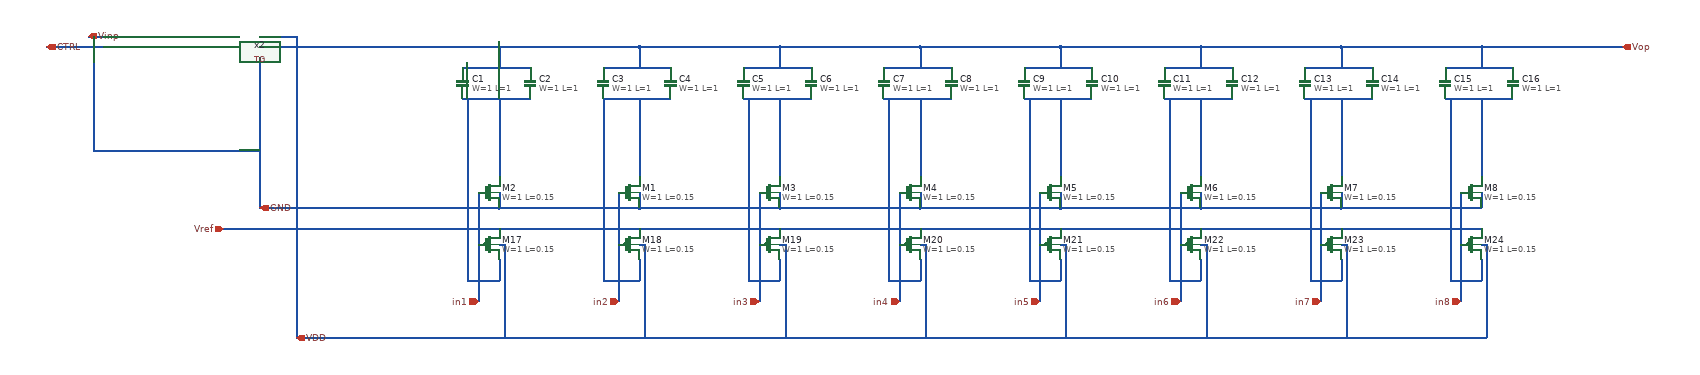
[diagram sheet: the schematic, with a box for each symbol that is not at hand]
v {xschem version=3.4.8RC file_version=1.2}
G {}
K {}
V {}
S {}
E {}
N -20 -30 110 -30 {lab=Vop}
N -20 30 110 30 {lab=#net1}
N 50 30 50 70 {lab=#net1}
N 50 -70 50 -30 {lab=Vop}
N 250 -30 380 -30 {lab=Vop}
N 250 30 380 30 {lab=#net2}
N 320 30 320 70 {lab=#net2}
N 320 -70 320 -30 {lab=Vop}
N 50 -70 320 -70 {lab=Vop}
N 320 -70 590 -70 {lab=Vop}
N 520 -30 650 -30 {lab=Vop}
N 520 30 650 30 {lab=#net3}
N 590 30 590 70 {lab=#net3}
N 590 -70 590 -30 {lab=Vop}
N 790 -30 920 -30 {lab=Vop}
N 790 30 920 30 {lab=#net4}
N 860 30 860 70 {lab=#net4}
N 860 -70 860 -30 {lab=Vop}
N 590 -70 860 -70 {lab=Vop}
N 860 -70 1130 -70 {lab=Vop}
N 1060 -30 1190 -30 {lab=Vop}
N 1060 30 1190 30 {lab=#net5}
N 1130 30 1130 70 {lab=#net5}
N 1130 -70 1130 -30 {lab=Vop}
N 1330 -30 1460 -30 {lab=Vop}
N 1330 30 1460 30 {lab=#net6}
N 1400 30 1400 70 {lab=#net6}
N 1400 -70 1400 -30 {lab=Vop}
N 1130 -70 1400 -70 {lab=Vop}
N 1400 -70 1670 -70 {lab=Vop}
N 1600 -30 1730 -30 {lab=Vop}
N 1600 30 1730 30 {lab=#net7}
N 1670 30 1670 70 {lab=#net7}
N 1670 -70 1670 -30 {lab=Vop}
N 1870 -30 2000 -30 {lab=Vop}
N 1870 30 2000 30 {lab=#net8}
N 1940 30 1940 70 {lab=#net8}
N 1940 -70 1940 -30 {lab=Vop}
N 1670 -70 1940 -70 {lab=Vop}
N 1940 -70 2210 -70 {lab=Vop}
N 50 70 50 180 {lab=#net1}
N 320 70 320 180 {lab=#net2}
N 590 70 590 180 {lab=#net3}
N 860 70 860 180 {lab=#net4}
N 1130 70 1130 180 {lab=#net5}
N 1400 70 1400 180 {lab=#net6}
N 1670 70 1670 180 {lab=#net7}
N 1940 70 1940 180 {lab=#net8}
N 50 240 320 240 {lab=Vinp}
N 320 240 590 240 {lab=Vinp}
N 590 240 860 240 {lab=Vinp}
N 860 240 1130 240 {lab=Vinp}
N 1130 240 1400 240 {lab=Vinp}
N 1400 240 1670 240 {lab=Vinp}
N 1670 240 1940 240 {lab=Vinp}
N 50 280 320 280 {lab=Vref}
N 320 280 590 280 {lab=Vref}
N 590 280 860 280 {lab=Vref}
N 860 280 1130 280 {lab=Vref}
N 1130 280 1400 280 {lab=Vref}
N 1400 280 1670 280 {lab=Vref}
N 1670 280 1940 280 {lab=Vref}
N 1940 340 1940 380 {lab=#net8}
N 1880 380 1940 380 {lab=#net8}
N 1880 30 1880 380 {lab=#net8}
N 1670 340 1670 380 {lab=#net7}
N 1610 380 1670 380 {lab=#net7}
N 1610 30 1610 380 {lab=#net7}
N 1400 340 1400 380 {lab=#net6}
N 1340 380 1400 380 {lab=#net6}
N 1340 30 1340 380 {lab=#net6}
N 1130 340 1130 380 {lab=#net5}
N 1070 380 1130 380 {lab=#net5}
N 1070 30 1070 380 {lab=#net5}
N 860 340 860 380 {lab=#net4}
N 800 380 860 380 {lab=#net4}
N 800 30 800 380 {lab=#net4}
N 590 340 590 380 {lab=#net3}
N 530 380 590 380 {lab=#net3}
N 530 30 530 380 {lab=#net3}
N 320 340 320 380 {lab=#net2}
N 250 380 320 380 {lab=#net2}
N 250 30 250 380 {lab=#net2}
N 50 340 50 380 {lab=#net1}
N -10 380 50 380 {lab=#net1}
N -10 30 -10 380 {lab=#net1}
N 1940 210 1940 240 {lab=Vinp}
N 50 210 50 240 {lab=Vinp}
N 320 210 320 240 {lab=Vinp}
N 590 210 590 240 {lab=Vinp}
N 860 210 860 240 {lab=Vinp}
N 1130 210 1130 240 {lab=Vinp}
N 1400 210 1400 240 {lab=Vinp}
N 1670 210 1670 240 {lab=Vinp}
N 10 290 10 310 {lab=in1}
N 1650 490 1920 490 {lab=VDD}
N 1380 490 1650 490 {lab=VDD}
N 1110 490 1380 490 {lab=VDD}
N 840 490 1110 490 {lab=VDD}
N 570 490 840 490 {lab=VDD}
N 300 490 570 490 {lab=VDD}
N 30 490 300 490 {lab=VDD}
N 1920 490 1950 490 {lab=VDD}
N 1950 310 1950 490 {lab=VDD}
N 1940 310 1950 310 {lab=VDD}
N 1670 310 1680 310 {lab=VDD}
N 1680 310 1680 490 {lab=VDD}
N 1400 310 1410 310 {lab=VDD}
N 1410 310 1410 490 {lab=VDD}
N 1130 310 1140 310 {lab=VDD}
N 1140 310 1140 490 {lab=VDD}
N 860 310 870 310 {lab=VDD}
N 870 310 870 490 {lab=VDD}
N 590 310 600 310 {lab=VDD}
N 600 310 600 490 {lab=VDD}
N 320 310 330 310 {lab=VDD}
N 330 310 330 490 {lab=VDD}
N 50 310 60 310 {lab=VDD}
N 60 310 60 490 {lab=VDD}
N -130 490 30 490 {lab=VDD}
N -410 -70 50 -70 {lab=Vop}
N -410 -50 -410 190 {lab=Vinp}
N -340 490 -130 490 {lab=VDD}
N -340 460 -340 490 {lab=VDD}
N -410 -90 -340 -90 {lab=VDD}
N -820 -70 -710 -70 {lab=CTRL}
N -340 -90 -340 460 {lab=VDD}
N -480 280 50 280 {lab=Vref}
N 10 210 10 290 {lab=in1}
N 10 310 10 420 {lab=in1}
N 280 290 280 310 {lab=in2}
N 280 210 280 290 {lab=in2}
N 280 310 280 420 {lab=in2}
N 550 290 550 310 {lab=in3}
N 550 210 550 290 {lab=in3}
N 550 310 550 420 {lab=in3}
N 820 290 820 310 {lab=in4}
N 820 210 820 290 {lab=in4}
N 820 310 820 420 {lab=in4}
N 1090 290 1090 310 {lab=in5}
N 1090 210 1090 290 {lab=in5}
N 1090 310 1090 420 {lab=in5}
N 1360 290 1360 310 {lab=in6}
N 1360 210 1360 290 {lab=in6}
N 1360 310 1360 420 {lab=in6}
N 1630 290 1630 310 {lab=in7}
N 1630 210 1630 290 {lab=in7}
N 1630 310 1630 420 {lab=in7}
N 1900 290 1900 310 {lab=in8}
N 1900 210 1900 290 {lab=in8}
N 1900 310 1900 420 {lab=in8}
N -410 240 50 240 {lab=Vinp}
N -410 190 -410 240 {lab=Vinp}
N -740 -90 -710 -90 {lab=Vinp}
N -730 -90 -730 130 {lab=Vinp}
N -730 130 -410 130 {lab=Vinp}
C {sky130_fd_pr/cap_mim_m3_1.sym} -20 0 0 0 {name=C1 model=cap_mim_m3_1 W=1 L=1 MF=128 spiceprefix=X}
C {sky130_fd_pr/cap_mim_m3_1.sym} 250 0 0 0 {name=C3 model=cap_mim_m3_1 W=1 L=1 MF=64 spiceprefix=X}
C {sky130_fd_pr/cap_mim_m3_1.sym} 380 0 0 0 {name=C4 model=cap_mim_m3_1 W=1 L=1 MF=64 spiceprefix=X}
C {sky130_fd_pr/cap_mim_m3_1.sym} 520 0 0 0 {name=C5 model=cap_mim_m3_1 W=1 L=1 MF=32 spiceprefix=X}
C {sky130_fd_pr/cap_mim_m3_1.sym} 650 0 0 0 {name=C6 model=cap_mim_m3_1 W=1 L=1 MF=32 spiceprefix=X}
C {sky130_fd_pr/cap_mim_m3_1.sym} 790 0 0 0 {name=C7 model=cap_mim_m3_1 W=1 L=1 MF=16 spiceprefix=X}
C {sky130_fd_pr/cap_mim_m3_1.sym} 920 0 0 0 {name=C8 model=cap_mim_m3_1 W=1 L=1 MF=16 spiceprefix=X}
C {sky130_fd_pr/cap_mim_m3_1.sym} 1060 0 0 0 {name=C9 model=cap_mim_m3_1 W=1 L=1 MF=8 spiceprefix=X}
C {sky130_fd_pr/cap_mim_m3_1.sym} 1190 0 0 0 {name=C10 model=cap_mim_m3_1 W=1 L=1 MF=8 spiceprefix=X}
C {sky130_fd_pr/cap_mim_m3_1.sym} 1330 0 0 0 {name=C11 model=cap_mim_m3_1 W=1 L=1 MF=4 spiceprefix=X}
C {sky130_fd_pr/cap_mim_m3_1.sym} 1460 0 0 0 {name=C12 model=cap_mim_m3_1 W=1 L=1 MF=4 spiceprefix=X}
C {sky130_fd_pr/cap_mim_m3_1.sym} 1600 0 0 0 {name=C13 model=cap_mim_m3_1 W=1 L=1 MF=2 spiceprefix=X}
C {sky130_fd_pr/cap_mim_m3_1.sym} 1730 0 0 0 {name=C14 model=cap_mim_m3_1 W=1 L=1 MF=2 spiceprefix=X}
C {sky130_fd_pr/cap_mim_m3_1.sym} 1870 0 0 0 {name=C15 model=cap_mim_m3_1 W=1 L=1 MF=1 spiceprefix=X}
C {sky130_fd_pr/cap_mim_m3_1.sym} 2000 0 0 0 {name=C16 model=cap_mim_m3_1 W=1 L=1 MF=1 spiceprefix=X}
C {sky130_fd_pr/nfet_01v8.sym} 30 210 0 0 {name=M2
L=0.15
W=1  
nf=1 mult=1
model=nfet_01v8
spiceprefix=X
}
C {sky130_fd_pr/nfet_01v8.sym} 300 210 0 0 {name=M1
L=0.15
W=1  
nf=1 mult=1
model=nfet_01v8
spiceprefix=X
}
C {sky130_fd_pr/nfet_01v8.sym} 570 210 0 0 {name=M3
L=0.15
W=1  
nf=1 mult=1
model=nfet_01v8
spiceprefix=X
}
C {sky130_fd_pr/nfet_01v8.sym} 840 210 0 0 {name=M4
L=0.15
W=1  
nf=1 mult=1
model=nfet_01v8
spiceprefix=X
}
C {sky130_fd_pr/nfet_01v8.sym} 1110 210 0 0 {name=M5
L=0.15
W=1  
nf=1 mult=1
model=nfet_01v8
spiceprefix=X
}
C {sky130_fd_pr/nfet_01v8.sym} 1380 210 0 0 {name=M6
L=0.15
W=1  
nf=1 mult=1
model=nfet_01v8
spiceprefix=X
}
C {sky130_fd_pr/nfet_01v8.sym} 1650 210 0 0 {name=M7
L=0.15
W=1  
nf=1 mult=1
model=nfet_01v8
spiceprefix=X
}
C {sky130_fd_pr/nfet_01v8.sym} 1920 210 0 0 {name=M8
L=0.15
W=1  
nf=1 mult=1
model=nfet_01v8
spiceprefix=X
}
C {sky130_fd_pr/pfet_01v8.sym} 30 310 2 1 {name=M17
L=0.15
W=1
nf=1 mult=1
model=pfet_01v8
spiceprefix=X
}
C {sky130_fd_pr/pfet_01v8.sym} 300 310 2 1 {name=M18
L=0.15
W=1
nf=1 mult=1
model=pfet_01v8
spiceprefix=X
}
C {sky130_fd_pr/pfet_01v8.sym} 570 310 2 1 {name=M19
L=0.15
W=1
nf=1 mult=1
model=pfet_01v8
spiceprefix=X
}
C {sky130_fd_pr/pfet_01v8.sym} 840 310 2 1 {name=M20
L=0.15
W=1
nf=1 mult=1
model=pfet_01v8
spiceprefix=X
}
C {sky130_fd_pr/pfet_01v8.sym} 1110 310 2 1 {name=M21
L=0.15
W=1
nf=1 mult=1
model=pfet_01v8
spiceprefix=X
}
C {sky130_fd_pr/pfet_01v8.sym} 1380 310 2 1 {name=M22
L=0.15
W=1
nf=1 mult=1
model=pfet_01v8
spiceprefix=X
}
C {sky130_fd_pr/pfet_01v8.sym} 1650 310 2 1 {name=M23
L=0.15
W=1
nf=1 mult=1
model=pfet_01v8
spiceprefix=X
}
C {sky130_fd_pr/pfet_01v8.sym} 1920 310 2 1 {name=M24
L=0.15
W=1
nf=1 mult=1
model=pfet_01v8
spiceprefix=X
}
C {ipin.sym} -480 280 0 0 {name=p2 lab=Vref}
C {iopin.sym} -340 490 0 1 {name=p3 lab=VDD}
C {iopin.sym} -740 -90 0 1 {name=p5 lab=Vinp}
C {opin.sym} 2210 -70 0 0 {name=p7 lab=Vop}
C {iopin.sym} -410 240 0 1 {name=p1 lab=GND}
C {TG.sym} -560 -70 0 0 {name=x2}
C {iopin.sym} -820 -70 0 1 {name=p8 lab=CTRL}
C {sky130_fd_pr/cap_mim_m3_1.sym} 110 0 0 0 {name=C2 model=cap_mim_m3_1 W=1 L=1 MF=128 spiceprefix=X}
C {ipin.sym} 10 420 0 0 {name=p4 lab=in1}
C {ipin.sym} 280 420 0 0 {name=p6 lab=in2}
C {ipin.sym} 550 420 0 0 {name=p9 lab=in3}
C {ipin.sym} 820 420 0 0 {name=p10 lab=in4}
C {ipin.sym} 1090 420 0 0 {name=p11 lab=in5}
C {ipin.sym} 1360 420 0 0 {name=p12 lab=in6}
C {ipin.sym} 1630 420 0 0 {name=p13 lab=in7}
C {ipin.sym} 1900 420 0 0 {name=p14 lab=in8}
